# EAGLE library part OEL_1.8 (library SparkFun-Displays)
WiseChip SSD1320 - 1.80" Flexible Grayscale OLED 1.80" 160*32 pixel flexible grayscale OLED display

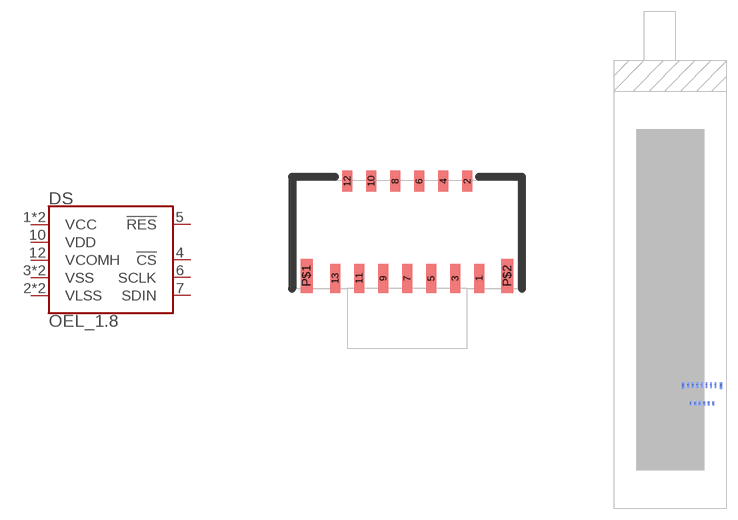
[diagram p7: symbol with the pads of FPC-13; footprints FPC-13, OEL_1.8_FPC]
Designator prefix DS

## OEL_1.8  [FPC-13]
1  VCC
2  VLSS
3  VSS
4  !CS!
5  !RES!
6  SCLK
7  SDIN
8  VSS
9  VLSS
10  VDD
12  VCOMH
13  VCC

## OEL_1.8OEL_1.8  [OEL_1.8_FPC]
Pads as for FPC-13

## OEL_1.8-AYF331335  [AYF331335]
1  VCC
2  VCOMH
4  VDD
5  VLSS
6  VSS
7  SDIN
8  SCLK
9  !RES!
10  !CS!
11  VSS
12  VLSS
13  VCC

## OEL_1.8OEL_Y3B (PROD_ID: LCD-13910, CONN-13933)  [OEL_1.8_FPC_Y3B]
Pads as for FPC-13

## Footprint FPC-13 (pad centres in mm)
FPC Connector - 13 Pin Example Datasheet
smd 0.25 x 0.72: 1 1.8,-1.265; 3 1.2,-1.265; 5 0.6,-1.265; 7 0,-1.265; 9 -0.6,-1.265; 11 -1.2,-1.265; 13 -1.8,-1.265
smd 0.25 x 0.52: 2 1.5,1.165; 4 0.9,1.165; 6 0.3,1.165; 8 -0.3,1.165; 10 -0.9,1.165; 12 -1.5,1.165
smd 0.3 x 0.85: P$1 -2.51,-1.2; P$2 2.51,-1.2

## Footprint OEL_1.8_FPC (pad centres in mm)
1.81" Greyscale OLED Includes FPC connector on bottom side and dimensions of display. bDoc outline indicates approximate location of the FPC cable.
smd 0.25 x 0.72 bottom: 1 6,-11.32; 3 5.4,-11.32; 5 4.8,-11.32; 7 4.2,-11.32; 9 3.6,-11.32; 11 3,-11.32; 13 2.4,-11.32
smd 0.25 x 0.52 bottom: 2 5.7,-13.75; 4 5.1,-13.75; 6 4.5,-13.75; 8 3.9,-13.75; 10 3.3,-13.75; 12 2.7,-13.75
smd 0.3 x 0.85 bottom: P$1 1.69,-11.385; P$2 6.71,-11.385

## Footprint AYF331335 (pad centres in mm)
Panasonic Y3B FPC Connector - 13 Pin Low-profile, top/bottom contact connector for 13-pin, 0.3mm pitch FPC connector. Datasheet
smd 0.23 x 0.44: 1 -1.8,1.355; 3 -1.2,1.355; 5 -0.6,1.355; 7 0,1.355; 9 0.6,1.355; 11 1.2,1.355; 13 1.8,1.355
smd 0.23 x 0.34: 2 -1.5,-1.405; 4 -0.9,-1.405; 6 -0.3,-1.405; 8 0.3,-1.405; 10 0.9,-1.405; 12 1.5,-1.405

## Footprint OEL_1.8_FPC_Y3B (pad centres in mm)
1.81" Greyscale OLED Includes Panasonic Y3B FPC connector on bottom side and dimensions of display. bDoc outline indicates approximate location of the FPC cable. Specifications: Pin count: 13 Pin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
smd 0.23 x 1 bottom: 1 6,-11.795; 2 5.7,-14.555; 3 5.4,-11.795; 4 5.1,-14.555; 5 4.8,-11.795; 6 4.5,-14.555; 7 4.2,-11.795; 8 3.9,-14.555; 9 3.6,-11.795; 10 3.3,-14.555; 11 3,-11.795; 12 2.7,-14.555; 13 2.4,-11.795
